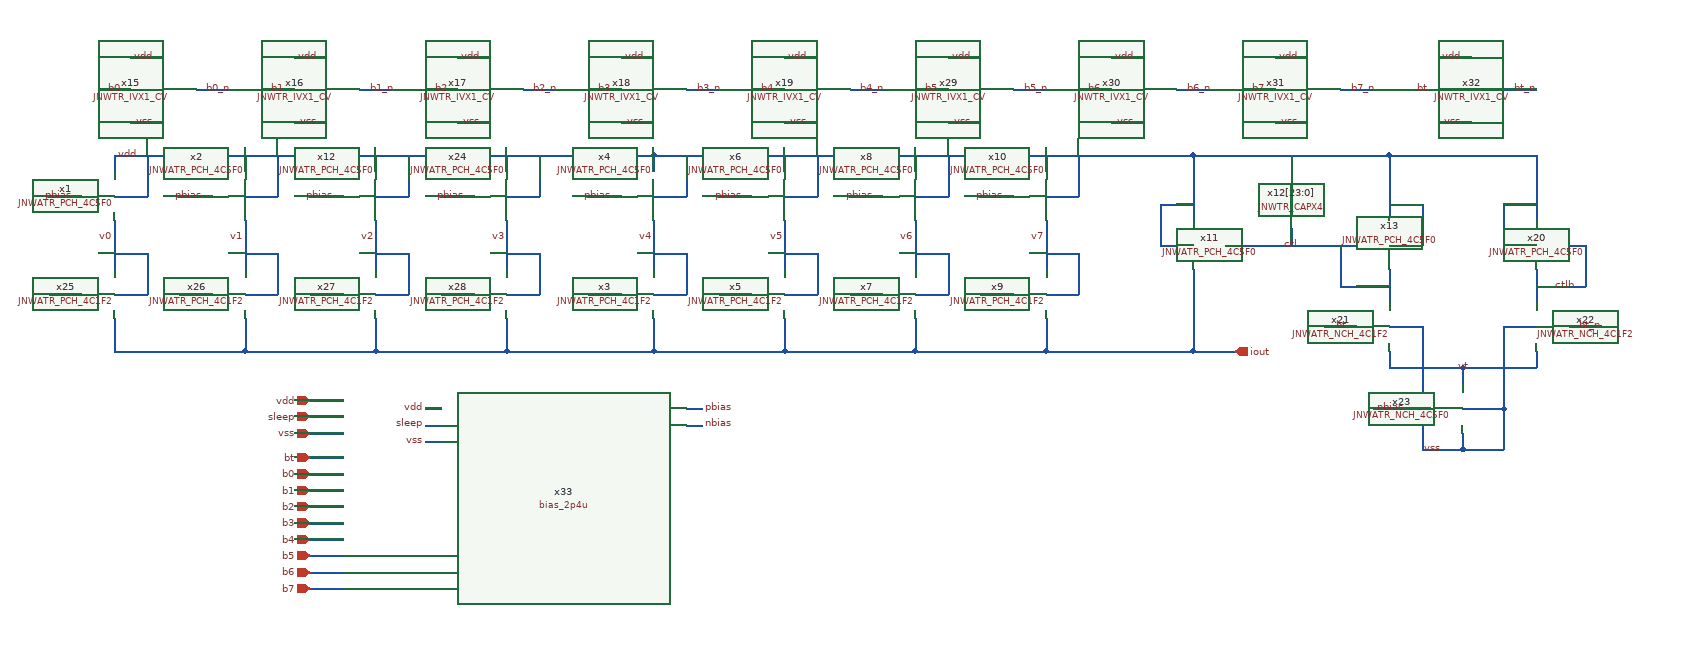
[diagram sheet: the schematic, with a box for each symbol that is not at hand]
v {xschem version=3.4.6 file_version=1.2}
G {}
K {}
V {}
S {}
E {}
N 520 350 560 350 {lab=pbias}
N 600 300 600 320 {lab=vdd}
N 600 380 600 440 {lab=v4}
N 600 500 600 540 {lab=iout}
N 520 470 560 470 {lab=b4_n}
N 600 350 640 350 {lab=vdd}
N 640 300 640 350 {lab=vdd}
N 600 470 640 470 {lab=v4}
N 640 420 640 470 {lab=v4}
N 600 420 640 420 {lab=v4}
N 600 540 760 540 {lab=iout}
N 680 350 720 350 {lab=pbias}
N 760 300 760 320 {lab=vdd}
N 760 380 760 440 {lab=v5}
N 760 500 760 540 {lab=iout}
N 680 470 720 470 {lab=b5_n}
N 760 350 800 350 {lab=vdd}
N 800 300 800 350 {lab=vdd}
N 760 470 800 470 {lab=v5}
N 800 420 800 470 {lab=v5}
N 760 420 800 420 {lab=v5}
N 760 540 920 540 {lab=iout}
N 840 350 880 350 {lab=pbias}
N 920 300 920 320 {lab=vdd}
N 920 380 920 440 {lab=v6}
N 920 500 920 540 {lab=iout}
N 840 470 880 470 {lab=b6_n}
N 920 350 960 350 {lab=vdd}
N 960 300 960 350 {lab=vdd}
N 920 470 960 470 {lab=v6}
N 960 420 960 470 {lab=v6}
N 920 420 960 420 {lab=v6}
N 920 540 1080 540 {lab=iout}
N 1000 350 1040 350 {lab=pbias}
N 1080 300 1080 320 {lab=vdd}
N 1080 380 1080 440 {lab=v7}
N 1080 500 1080 540 {lab=iout}
N 1000 470 1040 470 {lab=b7_n}
N 1080 350 1120 350 {lab=vdd}
N 1120 300 1120 350 {lab=vdd}
N 1080 470 1120 470 {lab=v7}
N 1120 420 1120 470 {lab=v7}
N 1080 420 1120 420 {lab=v7}
N 600 300 1260 300 {lab=vdd}
N -80 220 -40 220 {lab=b0}
N 180 710 220 710 {lab=b1}
N 180 730 220 730 {lab=b2}
N 180 750 220 750 {lab=b3}
N 180 770 220 770 {lab=b4}
N -40 180 0 180 {lab=vdd}
N -40 260 0 260 {lab=vss}
N 40 220 80 220 {lab=b0_n}
N 120 220 160 220 {lab=b1}
N 160 180 200 180 {lab=vdd}
N 160 260 200 260 {lab=vss}
N 240 220 280 220 {lab=b1_n}
N 320 220 360 220 {lab=b2}
N 360 180 400 180 {lab=vdd}
N 360 260 400 260 {lab=vss}
N 440 220 480 220 {lab=b2_n}
N 520 220 560 220 {lab=b3}
N 560 180 600 180 {lab=vdd}
N 560 260 600 260 {lab=vss}
N 640 220 680 220 {lab=b3_n}
N 720 220 760 220 {lab=b4}
N 760 180 800 180 {lab=vdd}
N 760 260 800 260 {lab=vss}
N 840 220 880 220 {lab=b4_n}
N 180 690 220 690 {lab=b0}
N 1300 410 1460 410 {lab=ctl}
N 1260 300 1260 380 {lab=vdd}
N 1080 540 1260 540 {lab=iout}
N 1380 390 1380 410 {lab=ctl}
N 1380 300 1380 320 {lab=vdd}
N 1260 300 1500 300 {lab=vdd}
N 1500 300 1500 380 {lab=vdd}
N 1500 410 1540 410 {lab=vdd}
N 1540 360 1540 410 {lab=vdd}
N 1500 360 1540 360 {lab=vdd}
N 1440 410 1440 460 {lab=ctl}
N 1440 460 1500 460 {lab=ctl}
N 1500 440 1500 480 {lab=ctl}
N 1720 410 1740 410 {lab=ctlb}
N 1680 300 1680 380 {lab=vdd}
N 1640 410 1680 410 {lab=vdd}
N 1640 360 1640 410 {lab=vdd}
N 1740 410 1740 460 {lab=ctlb}
N 1680 460 1740 460 {lab=ctlb}
N 1680 440 1680 480 {lab=ctlb}
N 1500 300 1680 300 {lab=vdd}
N 1640 360 1680 360 {lab=vdd}
N 1260 440 1260 540 {lab=iout}
N 1640 510 1680 510 {lab=vss}
N 1640 510 1640 610 {lab=vss}
N 1500 510 1540 510 {lab=vss}
N 1500 540 1500 560 {lab=vt}
N 1680 540 1680 560 {lab=vt}
N 1420 510 1460 510 {lab=bt}
N 1720 510 1760 510 {lab=bt_n}
N 1590 560 1590 580 {lab=vt}
N 1640 610 1640 660 {lab=vss}
N 1220 410 1260 410 {lab=vdd}
N 1220 360 1220 410 {lab=vdd}
N 1220 360 1260 360 {lab=vdd}
N 1590 640 1590 660 {lab=vss}
N 1590 610 1640 610 {lab=vss}
N 1590 660 1640 660 {lab=vss}
N 1480 610 1550 610 {lab=nbias}
N 1260 540 1310 540 {lab=iout}
N 180 620 220 620 {lab=sleep}
N 180 600 220 600 {lab=vdd}
N 180 640 220 640 {lab=vss}
N -140 350 -100 350 {lab=pbias}
N -60 300 -60 320 {lab=vdd}
N -60 380 -60 440 {lab=v0}
N -60 500 -60 540 {lab=iout}
N -140 470 -100 470 {lab=b0_n}
N -60 350 -20 350 {lab=vdd}
N -20 300 -20 350 {lab=vdd}
N -60 470 -20 470 {lab=v0}
N -20 420 -20 470 {lab=v0}
N -60 420 -20 420 {lab=v0}
N -60 540 100 540 {lab=iout}
N 20 350 60 350 {lab=pbias}
N 100 300 100 320 {lab=vdd}
N 100 380 100 440 {lab=v1}
N 100 500 100 540 {lab=iout}
N 20 470 60 470 {lab=b1_n}
N 100 350 140 350 {lab=vdd}
N 140 300 140 350 {lab=vdd}
N 100 470 140 470 {lab=v1}
N 140 420 140 470 {lab=v1}
N 100 420 140 420 {lab=v1}
N 100 540 260 540 {lab=iout}
N 180 350 220 350 {lab=pbias}
N 260 300 260 320 {lab=vdd}
N 260 380 260 440 {lab=v2}
N 260 500 260 540 {lab=iout}
N 180 470 220 470 {lab=b2_n}
N 260 350 300 350 {lab=vdd}
N 300 300 300 350 {lab=vdd}
N 260 470 300 470 {lab=v2}
N 300 420 300 470 {lab=v2}
N 260 420 300 420 {lab=v2}
N 260 540 420 540 {lab=iout}
N 340 350 380 350 {lab=pbias}
N 420 300 420 320 {lab=vdd}
N 420 380 420 440 {lab=v3}
N 420 500 420 540 {lab=iout}
N 340 470 380 470 {lab=b3_n}
N 420 350 460 350 {lab=vdd}
N 460 300 460 350 {lab=vdd}
N 420 470 460 470 {lab=v3}
N 460 420 460 470 {lab=v3}
N 420 420 460 420 {lab=v3}
N -60 300 600 300 {lab=vdd}
N 420 540 600 540 {lab=iout}
N 180 790 220 790 {lab=b5}
N 180 810 220 810 {lab=b6}
N 180 830 220 830 {lab=b7}
N 920 220 960 220 {lab=b5}
N 960 180 1000 180 {lab=vdd}
N 960 260 1000 260 {lab=vss}
N 1040 220 1080 220 {lab=b5_n}
N 1120 220 1160 220 {lab=b6}
N 1160 180 1200 180 {lab=vdd}
N 1160 260 1200 260 {lab=vss}
N 1240 220 1280 220 {lab=b6_n}
N 1320 220 1360 220 {lab=b7}
N 1360 180 1400 180 {lab=vdd}
N 1360 260 1400 260 {lab=vss}
N 1440 220 1480 220 {lab=b7_n}
N 1520 220 1560 220 {lab=bt}
N 1560 180 1600 180 {lab=vdd}
N 1560 260 1600 260 {lab=vss}
N 1640 220 1680 220 {lab=bt_n}
N 180 670 220 670 {lab=bt}
N 320 630 340 630 {lab=sleep}
N 640 630 660 630 {lab=nbias}
N 640 610 660 610 {lab=pbias}
N 320 650 340 650 {lab=vss}
N 320 610 340 610 {lab=vdd}
N 1540 510 1540 660 {lab=vss}
N 1500 560 1590 560 {lab=vt}
N 1590 560 1680 560 {lab=vt}
N 1540 660 1590 660 {lab=vss}
C {JNW_ATR_SKY130A/JNWATR_PCH_4C5F0.sym} 560 350 0 0 {name=x4 }
C {JNW_ATR_SKY130A/JNWATR_PCH_4C5F0.sym} 720 350 0 0 {name=x6 }
C {JNW_ATR_SKY130A/JNWATR_PCH_4C5F0.sym} 880 350 0 0 {name=x8 }
C {JNW_ATR_SKY130A/JNWATR_PCH_4C5F0.sym} 1040 350 0 0 {name=x10 }
C {devices/lab_wire.sym} 1030 470 0 0 {name=p3 sig_type=std_logic lab=b7_n
}
C {devices/lab_wire.sym} 870 470 0 0 {name=p4 sig_type=std_logic lab=b6_n
}
C {devices/lab_wire.sym} 710 470 0 0 {name=p5 sig_type=std_logic lab=b5_n
}
C {devices/lab_wire.sym} 550 470 0 0 {name=p6 sig_type=std_logic lab=b4_n
}
C {devices/ipin.sym} 180 600 0 0 {name=p14 lab=vdd}
C {devices/ipin.sym} 180 640 0 0 {name=p15 lab=vss}
C {devices/ipin.sym} 180 710 0 0 {name=p17 lab=b1}
C {devices/ipin.sym} 180 730 0 0 {name=p18 lab=b2}
C {devices/ipin.sym} 180 750 0 0 {name=p19 lab=b3}
C {devices/ipin.sym} 180 770 0 0 {name=p20 lab=b4}
C {JNW_TR_SKY130A/JNWTR_IVX1_CV.sym} -40 220 0 0 {name=x15 }
C {devices/lab_wire.sym} -10 260 2 1 {name=p23 sig_type=std_logic lab=vss}
C {devices/lab_wire.sym} -10 180 0 0 {name=p24 sig_type=std_logic lab=vdd}
C {JNW_TR_SKY130A/JNWTR_IVX1_CV.sym} 160 220 0 0 {name=x16 }
C {devices/lab_wire.sym} 190 260 2 1 {name=p26 sig_type=std_logic lab=vss}
C {devices/lab_wire.sym} 190 180 0 0 {name=p27 sig_type=std_logic lab=vdd}
C {JNW_TR_SKY130A/JNWTR_IVX1_CV.sym} 360 220 0 0 {name=x17 }
C {devices/lab_wire.sym} 390 260 2 1 {name=p30 sig_type=std_logic lab=vss}
C {devices/lab_wire.sym} 390 180 0 0 {name=p31 sig_type=std_logic lab=vdd}
C {JNW_TR_SKY130A/JNWTR_IVX1_CV.sym} 560 220 0 0 {name=x18 }
C {devices/lab_wire.sym} 590 260 2 1 {name=p34 sig_type=std_logic lab=vss}
C {devices/lab_wire.sym} 590 180 0 0 {name=p35 sig_type=std_logic lab=vdd}
C {JNW_TR_SKY130A/JNWTR_IVX1_CV.sym} 760 220 0 0 {name=x19 }
C {devices/lab_wire.sym} 790 260 2 1 {name=p38 sig_type=std_logic lab=vss}
C {devices/lab_wire.sym} 790 180 0 0 {name=p39 sig_type=std_logic lab=vdd}
C {devices/lab_wire.sym} -50 220 0 0 {name=p16 sig_type=std_logic lab=b0}
C {devices/lab_wire.sym} 550 220 0 0 {name=p25 sig_type=std_logic lab=b3}
C {devices/lab_wire.sym} 150 220 0 0 {name=p28 sig_type=std_logic lab=b1}
C {devices/lab_wire.sym} 750 220 0 0 {name=p29 sig_type=std_logic lab=b4}
C {devices/lab_wire.sym} 350 220 0 0 {name=p32 sig_type=std_logic lab=b2}
C {devices/ipin.sym} 180 690 0 0 {name=p7 lab=b0}
C {devices/lab_wire.sym} 650 220 0 1 {name=p36 sig_type=std_logic lab=b3_n}
C {devices/lab_wire.sym} 50 220 0 1 {name=p37 sig_type=std_logic lab=b0_n}
C {devices/lab_wire.sym} 250 220 0 1 {name=p40 sig_type=std_logic lab=b1_n}
C {devices/lab_wire.sym} 850 220 0 1 {name=p41 sig_type=std_logic lab=b4_n}
C {devices/lab_wire.sym} 450 220 0 1 {name=p45 sig_type=std_logic lab=b2_n}
C {devices/lab_wire.sym} 710 350 0 0 {name=p9 sig_type=std_logic lab=pbias
}
C {devices/lab_wire.sym} 870 350 0 0 {name=p8 sig_type=std_logic lab=pbias
}
C {devices/lab_wire.sym} 1030 350 0 0 {name=p10 sig_type=std_logic lab=pbias
}
C {devices/lab_wire.sym} 550 350 0 0 {name=p12 sig_type=std_logic lab=pbias
}
C {devices/ipin.sym} 180 620 0 0 {name=p33 lab=sleep}
C {JNW_ATR_SKY130A/JNWATR_PCH_4C5F0.sym} 1300 410 0 1 {name=x11 }
C {JNW_ATR_SKY130A/JNWATR_PCH_4C1F2.sym} 560 470 0 0 {name=x3 }
C {JNW_ATR_SKY130A/JNWATR_PCH_4C1F2.sym} 720 470 0 0 {name=x5 }
C {JNW_ATR_SKY130A/JNWATR_PCH_4C1F2.sym} 880 470 0 0 {name=x7 }
C {JNW_ATR_SKY130A/JNWATR_PCH_4C1F2.sym} 1040 470 0 0 {name=x9 }
C {JNW_TR_SKY130A/JNWTR_CAPX4.sym} 1380 380 0 0 {name=x12[23:0]}
C {JNW_ATR_SKY130A/JNWATR_PCH_4C5F0.sym} 1460 410 0 0 {name=x13 }
C {JNW_ATR_SKY130A/JNWATR_PCH_4C5F0.sym} 1720 410 0 1 {name=x20 }
C {JNW_ATR_SKY130A/JNWATR_NCH_4C1F2.sym} 1460 510 0 0 {name=x21 }
C {JNW_ATR_SKY130A/JNWATR_NCH_4C1F2.sym} 1720 510 0 1 {name=x22 }
C {devices/lab_wire.sym} 1730 510 0 1 {name=p1 sig_type=std_logic lab=bt_n}
C {devices/lab_wire.sym} 1450 510 0 0 {name=p2 sig_type=std_logic lab=bt}
C {JNW_ATR_SKY130A/JNWATR_NCH_4C5F0.sym} 1550 610 0 0 {name=x23 }
C {devices/lab_wire.sym} 1520 610 0 0 {name=p11 sig_type=std_logic lab=nbias
}
C {devices/lab_wire.sym} 1390 410 2 1 {name=p42 sig_type=std_logic lab=ctl
}
C {devices/lab_wire.sym} 1700 460 2 0 {name=p43 sig_type=std_logic lab=ctlb
}
C {devices/lab_wire.sym} 1600 560 0 0 {name=p44 sig_type=std_logic lab=vt}
C {devices/lab_wire.sym} 1080 400 2 1 {name=p46 sig_type=std_logic lab=v7}
C {devices/lab_wire.sym} 920 400 2 1 {name=p47 sig_type=std_logic lab=v6}
C {devices/lab_wire.sym} 760 400 2 1 {name=p48 sig_type=std_logic lab=v5}
C {devices/lab_wire.sym} 600 400 2 1 {name=p49 sig_type=std_logic lab=v4
}
C {devices/opin.sym} 1310 540 0 0 {name=p54 lab=iout}
C {devices/lab_wire.sym} 1540 660 0 1 {name=p52 sig_type=std_logic lab=vss
}
C {JNW_ATR_SKY130A/JNWATR_PCH_4C5F0.sym} -100 350 0 0 {name=x1 }
C {JNW_ATR_SKY130A/JNWATR_PCH_4C5F0.sym} 60 350 0 0 {name=x2 }
C {JNW_ATR_SKY130A/JNWATR_PCH_4C5F0.sym} 220 350 0 0 {name=x12 }
C {JNW_ATR_SKY130A/JNWATR_PCH_4C5F0.sym} 380 350 0 0 {name=x24 }
C {devices/lab_wire.sym} 370 470 0 0 {name=p55 sig_type=std_logic lab=b3_n
}
C {devices/lab_wire.sym} 210 470 0 0 {name=p56 sig_type=std_logic lab=b2_n
}
C {devices/lab_wire.sym} 50 470 0 0 {name=p57 sig_type=std_logic lab=b1_n
}
C {devices/lab_wire.sym} -110 470 0 0 {name=p58 sig_type=std_logic lab=b0_n
}
C {devices/lab_wire.sym} 50 350 0 0 {name=p59 sig_type=std_logic lab=pbias
}
C {devices/lab_wire.sym} 210 350 0 0 {name=p60 sig_type=std_logic lab=pbias
}
C {devices/lab_wire.sym} 370 350 0 0 {name=p61 sig_type=std_logic lab=pbias
}
C {devices/lab_wire.sym} -110 350 0 0 {name=p62 sig_type=std_logic lab=pbias
}
C {JNW_ATR_SKY130A/JNWATR_PCH_4C1F2.sym} -100 470 0 0 {name=x25 }
C {JNW_ATR_SKY130A/JNWATR_PCH_4C1F2.sym} 60 470 0 0 {name=x26 }
C {JNW_ATR_SKY130A/JNWATR_PCH_4C1F2.sym} 220 470 0 0 {name=x27 }
C {JNW_ATR_SKY130A/JNWATR_PCH_4C1F2.sym} 380 470 0 0 {name=x28 }
C {devices/lab_wire.sym} 420 400 2 1 {name=p63 sig_type=std_logic lab=v3}
C {devices/lab_wire.sym} 260 400 2 1 {name=p64 sig_type=std_logic lab=v2}
C {devices/lab_wire.sym} 100 400 2 1 {name=p65 sig_type=std_logic lab=v1}
C {devices/lab_wire.sym} -60 400 2 1 {name=p66 sig_type=std_logic lab=v0
}
C {devices/lab_wire.sym} -30 300 0 0 {name=p67 sig_type=std_logic lab=vdd
}
C {devices/ipin.sym} 180 790 0 0 {name=p22 lab=b5}
C {devices/ipin.sym} 180 810 0 0 {name=p68 lab=b6}
C {devices/ipin.sym} 180 830 0 0 {name=p69 lab=b7}
C {JNW_TR_SKY130A/JNWTR_IVX1_CV.sym} 960 220 0 0 {name=x29 }
C {devices/lab_wire.sym} 990 260 2 1 {name=p70 sig_type=std_logic lab=vss}
C {devices/lab_wire.sym} 990 180 0 0 {name=p71 sig_type=std_logic lab=vdd}
C {devices/lab_wire.sym} 950 220 0 0 {name=p72 sig_type=std_logic lab=b5}
C {devices/lab_wire.sym} 1050 220 0 1 {name=p73 sig_type=std_logic lab=b5_n}
C {JNW_TR_SKY130A/JNWTR_IVX1_CV.sym} 1160 220 0 0 {name=x30 }
C {devices/lab_wire.sym} 1190 260 2 1 {name=p74 sig_type=std_logic lab=vss}
C {devices/lab_wire.sym} 1190 180 0 0 {name=p75 sig_type=std_logic lab=vdd}
C {devices/lab_wire.sym} 1150 220 0 0 {name=p76 sig_type=std_logic lab=b6}
C {devices/lab_wire.sym} 1250 220 0 1 {name=p77 sig_type=std_logic lab=b6_n}
C {JNW_TR_SKY130A/JNWTR_IVX1_CV.sym} 1360 220 0 0 {name=x31 }
C {devices/lab_wire.sym} 1390 260 2 1 {name=p78 sig_type=std_logic lab=vss}
C {devices/lab_wire.sym} 1390 180 0 0 {name=p79 sig_type=std_logic lab=vdd}
C {devices/lab_wire.sym} 1350 220 0 0 {name=p80 sig_type=std_logic lab=b7}
C {devices/lab_wire.sym} 1450 220 0 1 {name=p81 sig_type=std_logic lab=b7_n}
C {JNW_TR_SKY130A/JNWTR_IVX1_CV.sym} 1560 220 0 0 {name=x32 }
C {devices/lab_wire.sym} 1590 260 2 1 {name=p82 sig_type=std_logic lab=vss}
C {devices/lab_wire.sym} 1590 180 0 0 {name=p83 sig_type=std_logic lab=vdd}
C {devices/lab_wire.sym} 1550 220 0 0 {name=p84 sig_type=std_logic lab=bt}
C {devices/lab_wire.sym} 1650 220 0 1 {name=p85 sig_type=std_logic lab=bt_n}
C {devices/ipin.sym} 180 670 0 0 {name=p86 lab=bt}
C {devices/lab_wire.sym} 660 610 0 1 {name=p87 sig_type=std_logic lab=pbias
}
C {devices/lab_wire.sym} 660 630 0 1 {name=p88 sig_type=std_logic lab=nbias
}
C {devices/lab_wire.sym} 320 650 0 0 {name=p89 sig_type=std_logic lab=vss
}
C {devices/lab_wire.sym} 320 610 0 0 {name=p90 sig_type=std_logic lab=vdd
}
C {devices/lab_wire.sym} 320 630 0 0 {name=p91 sig_type=std_logic lab=sleep
}
C {LELO_TORD_SKY130A/bias_2p4u.sym} 490 630 0 0 {name=x33}
